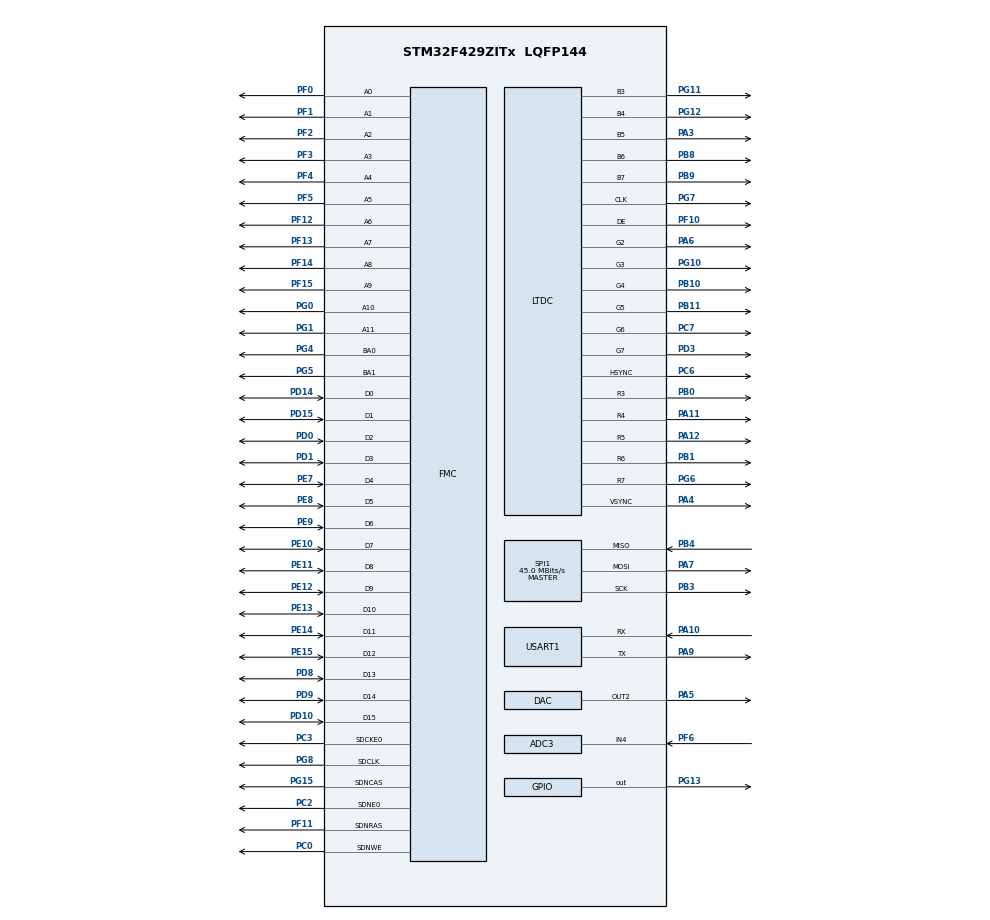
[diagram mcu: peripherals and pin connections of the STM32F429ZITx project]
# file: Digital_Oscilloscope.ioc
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ADC3.Channel-0\#ChannelRegularConversion=ADC_CHANNEL_4
ADC3.ClockPrescaler=ADC_CLOCK_SYNC_PCLK_DIV8
ADC3.ContinuousConvMode=ENABLE
ADC3.DMAContinuousRequests=ENABLE
ADC3.NbrOfConversionFlag=1
ADC3.Rank-0\#ChannelRegularConversion=1
ADC3.SamplingTime-0\#ChannelRegularConversion=ADC_SAMPLETIME_480CYCLES
DAC.DAC_Trigger2=DAC_TRIGGER_T6_TRGO
Dma.ADC3.0.Direction=DMA_PERIPH_TO_MEMORY
Dma.ADC3.0.FIFOMode=DMA_FIFOMODE_DISABLE
Dma.ADC3.0.Instance=DMA2_Stream0
Dma.ADC3.0.MemDataAlignment=DMA_MDATAALIGN_HALFWORD
Dma.ADC3.0.MemInc=DMA_MINC_ENABLE
Dma.ADC3.0.Mode=DMA_CIRCULAR
Dma.ADC3.0.PeriphDataAlignment=DMA_PDATAALIGN_HALFWORD
Dma.ADC3.0.PeriphInc=DMA_PINC_DISABLE
Dma.ADC3.0.Priority=DMA_PRIORITY_LOW
Dma.DAC2.1.Direction=DMA_MEMORY_TO_PERIPH
Dma.DAC2.1.FIFOMode=DMA_FIFOMODE_DISABLE
Dma.DAC2.1.Instance=DMA1_Stream6
Dma.DAC2.1.MemDataAlignment=DMA_MDATAALIGN_WORD
Dma.DAC2.1.MemInc=DMA_MINC_ENABLE
Dma.DAC2.1.Mode=DMA_CIRCULAR
Dma.DAC2.1.PeriphDataAlignment=DMA_PDATAALIGN_WORD
Dma.DAC2.1.PeriphInc=DMA_PINC_DISABLE
Dma.DAC2.1.Priority=DMA_PRIORITY_LOW
Dma.Request0=ADC3
Dma.Request1=DAC2
Mcu.Family=STM32F4
Mcu.Name=STM32F429ZITx
Mcu.Package=LQFP144
NVIC.DMA1_Stream6_IRQn=true\:0\:0\:false\:false\:true\:false\:true
NVIC.DMA2_Stream0_IRQn=true\:0\:0\:false\:false\:true\:false\:true
NVIC.PriorityGroup=NVIC_PRIORITYGROUP_4
NVIC.TIM6_DAC_IRQn=true\:0\:0\:false\:false\:true\:true\:true
NVIC.USART1_IRQn=true\:0\:0\:false\:false\:true\:true\:true
PA10.Mode=Asynchronous
PA10.Signal=USART1_RX
PA11.Mode=RGB565
PA11.Signal=LTDC_R4
PA12.Mode=RGB565
PA12.Signal=LTDC_R5
PA3.Mode=RGB565
PA3.Signal=LTDC_B5
PA4.Mode=RGB565
PA4.Signal=LTDC_VSYNC
PA5.Signal=COMP_DAC2_group
PA6.Mode=RGB565
PA6.Signal=LTDC_G2
PA7.Mode=Full_Duplex_Master
PA7.Signal=SPI1_MOSI
PA9.Mode=Asynchronous
PA9.Signal=USART1_TX
PB0.Mode=RGB565
PB0.Signal=LTDC_R3
PB1.Mode=RGB565
PB1.Signal=LTDC_R6
PB10.Mode=RGB565
PB10.Signal=LTDC_G4
PB11.Mode=RGB565
PB11.Signal=LTDC_G5
PB3.Mode=Full_Duplex_Master
PB3.Signal=SPI1_SCK
PB4.Mode=Full_Duplex_Master
PB4.Signal=SPI1_MISO
PB8.Mode=RGB565
PB8.Signal=LTDC_B6
PB9.Mode=RGB565
PB9.Signal=LTDC_B7
PC0.Signal=FMC_SDNWE
PC2.Mode=SdramChipSelect1_1
PC2.Signal=FMC_SDNE0
PC3.Mode=SdramChipSelect1_1
PC3.Signal=FMC_SDCKE0
PC6.Mode=RGB565
PC6.Signal=LTDC_HSYNC
PC7.Mode=RGB565
PC7.Signal=LTDC_G6
PD0.Signal=FMC_D2_DA2
PD1.Signal=FMC_D3_DA3
PD10.Signal=FMC_D15_DA15
PD14.Signal=FMC_D0_DA0
PD15.Signal=FMC_D1_DA1
PD3.Mode=RGB565
PD3.Signal=LTDC_G7
PD8.Signal=FMC_D13_DA13
PD9.Signal=FMC_D14_DA14
PE10.Signal=FMC_D7_DA7
PE11.Signal=FMC_D8_DA8
PE12.Signal=FMC_D9_DA9
PE13.Signal=FMC_D10_DA10
PE14.Signal=FMC_D11_DA11
PE15.Signal=FMC_D12_DA12
PE7.Signal=FMC_D4_DA4
PE8.Signal=FMC_D5_DA5
PE9.Signal=FMC_D6_DA6
PF0.Signal=FMC_A0
PF1.Signal=FMC_A1
PF10.Mode=RGB565
PF10.Signal=LTDC_DE
PF11.Signal=FMC_SDNRAS
PF12.Signal=FMC_A6
PF13.Signal=FMC_A7
PF14.Signal=FMC_A8
PF15.Signal=FMC_A9
PF2.Signal=FMC_A2
PF3.Signal=FMC_A3
PF4.Signal=FMC_A4
PF5.Signal=FMC_A5
PF6.Mode=IN4
PF6.Signal=ADC3_IN4
PG0.Signal=FMC_A10
PG1.Signal=FMC_A11
PG10.Mode=RGB565
PG10.Signal=LTDC_G3
PG11.Mode=RGB565
PG11.Signal=LTDC_B3
PG12.Mode=RGB565
PG12.Signal=LTDC_B4
PG13.GPIO_Speed=GPIO_SPEED_FREQ_VERY_HIGH
PG13.Signal=GPIO_Output
PG15.Signal=FMC_SDNCAS
PG4.Signal=FMC_A14_BA0
PG5.Signal=FMC_A15_BA1
PG6.Mode=RGB565
PG6.Signal=LTDC_R7
PG7.Mode=RGB565
PG7.Signal=LTDC_CLK
PG8.Signal=FMC_SDCLK
PH0/OSC_IN.Mode=HSE-External-Oscillator
PH0/OSC_IN.Signal=RCC_OSC_IN
PH1/OSC_OUT.Mode=HSE-External-Oscillator
PH1/OSC_OUT.Signal=RCC_OSC_OUT
ProjectManager.HeapSize=0x200
ProjectManager.StackSize=0x400
ProjectManager.TargetToolchain=STM32CubeIDE
RCC.48MHZClocksFreq_Value=90000000
RCC.AHBFreq_Value=180000000
RCC.APB1CLKDivider=RCC_HCLK_DIV4
RCC.APB1Freq_Value=45000000
RCC.APB1TimFreq_Value=90000000
RCC.APB2CLKDivider=RCC_HCLK_DIV2
RCC.APB2Freq_Value=90000000
RCC.APB2TimFreq_Value=180000000
RCC.CortexFreq_Value=180000000
RCC.HCLKFreq_Value=180000000
RCC.HSE_VALUE=8000000
RCC.HSI_VALUE=16000000
RCC.LSE_VALUE=32768
RCC.PLLM=8
RCC.PLLN=360
RCC.PLLSAIDivR=RCC_PLLSAIDIVR_8
RCC.PLLSAIN=192
RCC.PLLSAIR=4
RCC.PLLSourceVirtual=RCC_PLLSOURCE_HSE
RCC.SYSCLKFreq_VALUE=180000000
RCC.SYSCLKSource=RCC_SYSCLKSOURCE_PLLCLK
RCC.VCOOutputFreq_Value=360000000
SH.COMP_DAC2_group.0=DAC_OUT2,DAC_OUT2
SH.FMC_A0.0=FMC_A0,12b-sda1
SH.FMC_A1.0=FMC_A1,12b-sda1
SH.FMC_A10.0=FMC_A10,12b-sda1
SH.FMC_A11.0=FMC_A11,12b-sda1
SH.FMC_A14_BA0.0=FMC_BA0,FourSdramBanks1
SH.FMC_A15_BA1.0=FMC_BA1,FourSdramBanks1
SH.FMC_A2.0=FMC_A2,12b-sda1
SH.FMC_A3.0=FMC_A3,12b-sda1
SH.FMC_A4.0=FMC_A4,12b-sda1
SH.FMC_A5.0=FMC_A5,12b-sda1
SH.FMC_A6.0=FMC_A6,12b-sda1
SH.FMC_A7.0=FMC_A7,12b-sda1
SH.FMC_A8.0=FMC_A8,12b-sda1
SH.FMC_A9.0=FMC_A9,12b-sda1
SH.FMC_D0_DA0.0=FMC_D0,sd-16b-d1
SH.FMC_D10_DA10.0=FMC_D10,sd-16b-d1
SH.FMC_D11_DA11.0=FMC_D11,sd-16b-d1
SH.FMC_D12_DA12.0=FMC_D12,sd-16b-d1
SH.FMC_D13_DA13.0=FMC_D13,sd-16b-d1
SH.FMC_D14_DA14.0=FMC_D14,sd-16b-d1
SH.FMC_D15_DA15.0=FMC_D15,sd-16b-d1
SH.FMC_D1_DA1.0=FMC_D1,sd-16b-d1
SH.FMC_D2_DA2.0=FMC_D2,sd-16b-d1
SH.FMC_D3_DA3.0=FMC_D3,sd-16b-d1
SH.FMC_D4_DA4.0=FMC_D4,sd-16b-d1
SH.FMC_D5_DA5.0=FMC_D5,sd-16b-d1
SH.FMC_D6_DA6.0=FMC_D6,sd-16b-d1
SH.FMC_D7_DA7.0=FMC_D7,sd-16b-d1
SH.FMC_D8_DA8.0=FMC_D8,sd-16b-d1
SH.FMC_D9_DA9.0=FMC_D9,sd-16b-d1
SH.FMC_SDCLK.0=FMC_SDCLK,12b-sda1
SH.FMC_SDNCAS.0=FMC_SDNCAS,12b-sda1
SH.FMC_SDNRAS.0=FMC_SDNRAS,12b-sda1
SH.FMC_SDNWE.0=FMC_SDNWE,12b-sda1
SPI1.CalculateBaudRate=45.0 MBits/s
SPI1.Direction=SPI_DIRECTION_2LINES
SPI1.Mode=SPI_MODE_MASTER
SPI1.VirtualType=VM_MASTER
TIM6.Period=100-1
TIM6.Prescaler=90-1
TIM6.TIM_MasterOutputTrigger=TIM_TRGO_UPDATE
USART1.VirtualMode=VM_ASYNC
VP_DMA2D_VS_DMA2D.Mode=DMA2D_Activate
VP_TIM6_VS_ClockSourceINT.Mode=Enable_Timer
board=custom

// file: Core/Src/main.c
/* USER CODE BEGIN Header */
/**
  ******************************************************************************
  * @file           : main.c
  * @brief          : Main program body
  ******************************************************************************
  * @attention
  *
  * <h2><center>&copy; Copyright (c) 2021 STMicroelectronics.
  * All rights reserved.</center></h2>
  *
  * This software component is licensed by ST under BSD 3-Clause license,
  * the "License"; You may not use this file except in compliance with the
  * License. You may obtain a copy of the License at:
  *                        opensource.org/licenses/BSD-3-Clause
  *
  ******************************************************************************
  */
/* USER CODE END Header */
#include "main.h"
#include "adc.h"
#include "dac.h"
#include "dma.h"
#include "dma2d.h"
#include "spi.h"
#include "tim.h"
#include "usart.h"
#include "gpio.h"
#include "fmc.h"

/* USER CODE BEGIN Includes */
#include "signal_matlab.h"
#include "lcd.h"
#include <math.h>
/* USER CODE END Includes */

void SystemClock_Config(void);

int main(void)
{

  /* MCU Configuration--------------------------------------------------------*/

  /* Reset of all peripherals, Initializes the Flash interface and the Systick. */
  HAL_Init();

  /* Configure the system clock */
  SystemClock_Config();

  /* USER CODE BEGIN SysInit */
  //MX_SPI1_Init();
  StartScreen();
  /* USER CODE END SysInit */

  /* Initialize all configured peripherals */
  MX_GPIO_Init();
  MX_DMA_Init();
  MX_DMA2D_Init();
  MX_FMC_Init();
  MX_SPI1_Init();
  MX_ADC3_Init();
  MX_DAC_Init();
  MX_USART1_UART_Init();
  MX_TIM6_Init();
  /* USER CODE BEGIN 2 */
  int stanje = 0;
  int stanjeFiltra = 2;
  start_timer();
  if(HAL_ADC_Start_DMA(&hadc3, (uint32_t*)&buffer, BUFFER_SIZE) != HAL_OK)
    {
      /* Start Conversation Error */
      Error_Handler();
    }

  for(int i = 0; i < BUFFER_SIZE; i++){
	  arrayFormer[i] = 0;
  }

  /* USER CODE END 2 */

  /* Infinite loop */
  /* USER CODE BEGIN WHILE */
  while (1)
  {

	  adjust(&stanje, &stanjeFiltra);

    /* USER CODE END WHILE */

  }
}

void SystemClock_Config(void)
{
  RCC_OscInitTypeDef RCC_OscInitStruct = {0};
  RCC_ClkInitTypeDef RCC_ClkInitStruct = {0};
  RCC_PeriphCLKInitTypeDef PeriphClkInitStruct = {0};

  /** Configure the main internal regulator output voltage
  */
  __HAL_RCC_PWR_CLK_ENABLE();
  __HAL_PWR_VOLTAGESCALING_CONFIG(PWR_REGULATOR_VOLTAGE_SCALE1);
  /** Initializes the RCC Oscillators according to the specified parameters
  * in the RCC_OscInitTypeDef structure.
  */
  RCC_OscInitStruct.OscillatorType = RCC_OSCILLATORTYPE_HSE;
  RCC_OscInitStruct.HSEState = RCC_HSE_ON;
  RCC_OscInitStruct.PLL.PLLState = RCC_PLL_ON;
  RCC_OscInitStruct.PLL.PLLSource = RCC_PLLSOURCE_HSE;
  RCC_OscInitStruct.PLL.PLLM = 8;
  RCC_OscInitStruct.PLL.PLLN = 360;
  RCC_OscInitStruct.PLL.PLLP = RCC_PLLP_DIV2;
  RCC_OscInitStruct.PLL.PLLQ = 4;
  if (HAL_RCC_OscConfig(&RCC_OscInitStruct) != HAL_OK)
  {
    Error_Handler();
  }
  /** Activate the Over-Drive mode
  */
  if (HAL_PWREx_EnableOverDrive() != HAL_OK)
  {
    Error_Handler();
  }
  /** Initializes the CPU, AHB and APB buses clocks
  */
  RCC_ClkInitStruct.ClockType = RCC_CLOCKTYPE_HCLK|RCC_CLOCKTYPE_SYSCLK
                              |RCC_CLOCKTYPE_PCLK1|RCC_CLOCKTYPE_PCLK2;
  RCC_ClkInitStruct.SYSCLKSource = RCC_SYSCLKSOURCE_PLLCLK;
  RCC_ClkInitStruct.AHBCLKDivider = RCC_SYSCLK_DIV1;
  RCC_ClkInitStruct.APB1CLKDivider = RCC_HCLK_DIV4;
  RCC_ClkInitStruct.APB2CLKDivider = RCC_HCLK_DIV8;

  if (HAL_RCC_ClockConfig(&RCC_ClkInitStruct, FLASH_LATENCY_5) != HAL_OK)
  {
    Error_Handler();
  }
  PeriphClkInitStruct.PeriphClockSelection = RCC_PERIPHCLK_LTDC;
  PeriphClkInitStruct.PLLSAI.PLLSAIN = 192;
  PeriphClkInitStruct.PLLSAI.PLLSAIR = 4;
  PeriphClkInitStruct.PLLSAIDivR = RCC_PLLSAIDIVR_8;
  if (HAL_RCCEx_PeriphCLKConfig(&PeriphClkInitStruct) != HAL_OK)
  {
    Error_Handler();
  }
}

/* USER CODE BEGIN 4 */
void adjust(int* stanje, int* stanjeFiltra){
	if(!signal_q) {
		if(filtered){
			if(*stanje != 1){
				ChangeTitle("Filtered Spectrum");
				*stanje = 1;
			}
		}else{
			if(*stanje != 2){
				ChangeTitle("Spectrum");
				*stanje = 2;
			}
		}
	}else{
		if(filtered){
			if(*stanje != 3){
				ChangeTitle("Filtered Signal");
				*stanje = 3;
			}
		}else{
			if(*stanje != 4){
				ChangeTitle("Signal");
				*stanje = 4;
			}
		}
	}
	if(lowpass){
		if(*stanjeFiltra != 0){
			SetFilter(0);
			*stanjeFiltra = 0;
		}
	}else{
		if(*stanjeFiltra != 1){
			SetFilter(1);
			*stanjeFiltra = 1;
		}
	}

	generate();
	cutOffSetup();
}
/* USER CODE END 4 */

void Error_Handler(void)
{
  __disable_irq();
  while (1)
  {
  }
}

/************************ (C) COPYRIGHT STMicroelectronics *****END OF FILE****/
